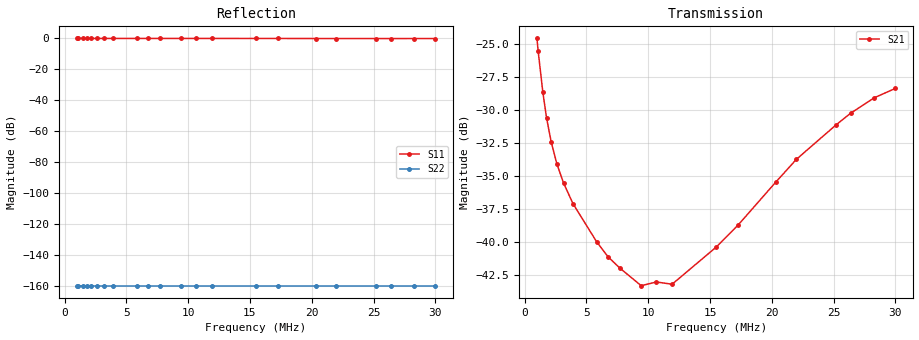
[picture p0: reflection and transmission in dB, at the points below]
! ListType=Lin
!!2xFT240-43 2x12t AWG12 shorted
# MHZ S RI R 50
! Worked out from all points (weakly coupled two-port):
!   4092 points, 1 MHz to 30 MHz, reference 50 ohm
!   highest |S21| = -24.56 dB at 1 MHz (marker M1); lowest = -43.3 dB at 9.436 MHz (marker M2)
!   lowest |S11| = -0.2 dB at 26.41 MHz (marker M3), VSWR 108.90, Z = 193 - j1e+03 ohm
!   |S11| at or under -10 dB: nowhere
!   S12 and S22 are empty: the file has one direction only
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1  0.9942 0.0553  0.00691 -0.0587  0 0  0 0
1.099242  0.9945 0.0489  0.00641 -0.0526  0 0  0 0
1.474945  0.9948 0.0318  0.00629 -0.0366  0 0  0 0
1.77976  0.9939 0.0231  0.00709 -0.0287  0 0  0 0
2.155463  0.9923 0.0156  0.00805 -0.0226  0 0  0 0
2.609142  0.9917 0.00952  0.00878 -0.0178  0 0  0 0
3.154974  0.9915 0.00433  0.00924 -0.014  0 0  0 0
3.920557  0.9911 -0.00135  0.00938 -0.0104  0 0  0 0
5.834515  0.9909 -0.0132  0.0088 -0.00485  0 0  0 0
6.75605  0.991 -0.0178  0.00834 -0.00287  0 0  0 0
7.713029  0.9908 -0.0226  0.0079 -0.0012  0 0  0 0
9.43559  0.9902 -0.0308  0.00664 0.00172  0 0  0 0
10.66903  0.9902 -0.0364  0.00631 0.00322  0 0  0 0
11.93791  0.9892 -0.0418  0.00506 0.00476  0 0  0 0
15.50354  0.9868 -0.0572  0.00217 0.00935  0 0  0 0
17.25446  0.9852 -0.0639  0.000216 0.0116  0 0  0 0
20.33806  0.9819 -0.0751  -0.00382 0.0165  0 0  0 0
21.99682  0.9802 -0.0803  -0.00578 0.0198  0 0  0 0
25.17257  0.9783 -0.0905  -0.00916 0.0262  0 0  0 0
26.40601  0.9773 -0.0941  -0.0103 0.0291  0 0  0 0
28.30579  0.9776 -0.1  -0.0113 0.0334  0 0  0 0
30  0.9777 -0.1065  -0.0117 0.0364  0 0  0 0
